One B-rep face of a CAD part: STEP entity #770179.
In plain terms, the planar face has unit normal (0, 0, 1).
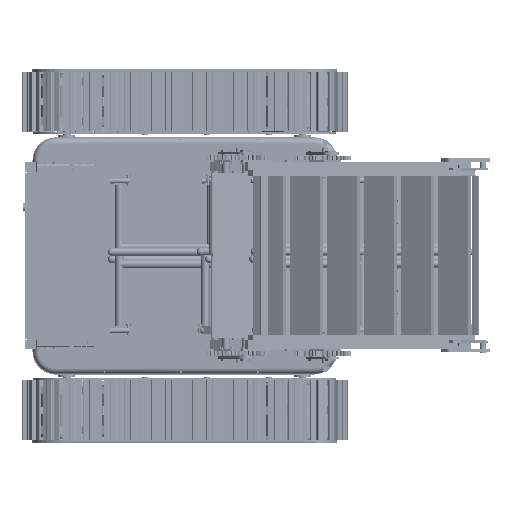
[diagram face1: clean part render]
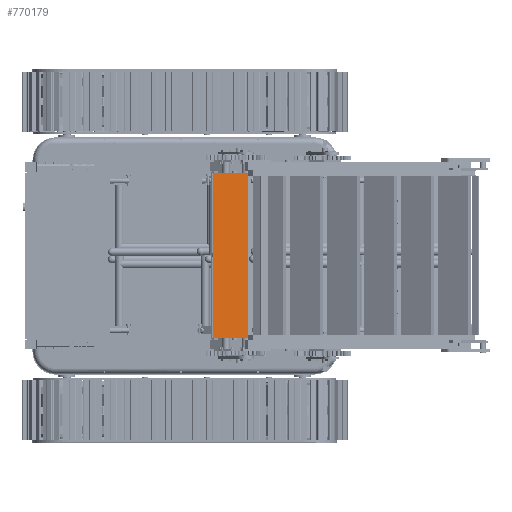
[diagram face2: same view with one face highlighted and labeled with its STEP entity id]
Length unit declared in the file: centimetre
Its self-contained STEP definition (entity closure, numbers rounded to 3 decimals, lengths and spline knots to 4 decimals):
#769865 = VERTEX_POINT('',#769866);
#769866 = CARTESIAN_POINT('',(-19.,-44.,10.));
#769873 = PLANE('',#769874);
#769874 = AXIS2_PLACEMENT_3D('',#769875,#769876,#769877);
#769875 = CARTESIAN_POINT('',(-19.,-44.,9.2));
#769876 = DIRECTION('',(1.,0.,0.));
#769877 = DIRECTION('',(0.,0.,1.));
#769885 = PLANE('',#769886);
#769886 = AXIS2_PLACEMENT_3D('',#769887,#769888,#769889);
#769887 = CARTESIAN_POINT('',(-19.,-44.,9.2));
#769888 = DIRECTION('',(0.,1.,0.));
#769889 = DIRECTION('',(0.,0.,1.));
#769926 = VERTEX_POINT('',#769927);
#769927 = CARTESIAN_POINT('',(-19.,44.,10.));
#769941 = PLANE('',#769942);
#769942 = AXIS2_PLACEMENT_3D('',#769943,#769944,#769945);
#769943 = CARTESIAN_POINT('',(-19.,44.,9.2));
#769944 = DIRECTION('',(0.,1.,0.));
#769945 = DIRECTION('',(0.,0.,1.));
#769953 = EDGE_CURVE('',#769865,#769926,#769954,.T.);
#769954 = SURFACE_CURVE('',#769955,(#769959,#769966),.PCURVE_S1.);
#769955 = LINE('',#769956,#769957);
#769956 = CARTESIAN_POINT('',(-19.,-44.,10.));
#769957 = VECTOR('',#769958,0.1);
#769958 = DIRECTION('',(0.,1.,0.));
#769959 = PCURVE('',#769873,#769960);
#769960 = DEFINITIONAL_REPRESENTATION('',(#769961),#769965);
#769961 = LINE('',#769962,#769963);
#769962 = CARTESIAN_POINT('',(0.8,0.));
#769963 = VECTOR('',#769964,1.);
#769964 = DIRECTION('',(0.,-1.));
#769965 = ( GEOMETRIC_REPRESENTATION_CONTEXT(2) 
PARAMETRIC_REPRESENTATION_CONTEXT() REPRESENTATION_CONTEXT('2D SPACE',''
  ) );
#769966 = PCURVE('',#769967,#769972);
#769967 = PLANE('',#769968);
#769968 = AXIS2_PLACEMENT_3D('',#769969,#769970,#769971);
#769969 = CARTESIAN_POINT('',(-19.,-44.,10.));
#769970 = DIRECTION('',(0.,0.,1.));
#769971 = DIRECTION('',(1.,0.,0.));
#769972 = DEFINITIONAL_REPRESENTATION('',(#769973),#769977);
#769973 = LINE('',#769974,#769975);
#769974 = CARTESIAN_POINT('',(0.,0.));
#769975 = VECTOR('',#769976,1.);
#769976 = DIRECTION('',(0.,1.));
#769977 = ( GEOMETRIC_REPRESENTATION_CONTEXT(2) 
PARAMETRIC_REPRESENTATION_CONTEXT() REPRESENTATION_CONTEXT('2D SPACE',''
  ) );
#769985 = VERTEX_POINT('',#769986);
#769986 = CARTESIAN_POINT('',(0.,-44.,10.));
#769993 = PLANE('',#769994);
#769994 = AXIS2_PLACEMENT_3D('',#769995,#769996,#769997);
#769995 = CARTESIAN_POINT('',(0.,-44.,9.2));
#769996 = DIRECTION('',(1.,0.,0.));
#769997 = DIRECTION('',(0.,0.,1.));
#770036 = VERTEX_POINT('',#770037);
#770037 = CARTESIAN_POINT('',(0.,44.,10.));
#770058 = EDGE_CURVE('',#769985,#770036,#770059,.T.);
#770059 = SURFACE_CURVE('',#770060,(#770064,#770071),.PCURVE_S1.);
#770060 = LINE('',#770061,#770062);
#770061 = CARTESIAN_POINT('',(0.,-44.,10.));
#770062 = VECTOR('',#770063,0.1);
#770063 = DIRECTION('',(0.,1.,0.));
#770064 = PCURVE('',#769993,#770065);
#770065 = DEFINITIONAL_REPRESENTATION('',(#770066),#770070);
#770066 = LINE('',#770067,#770068);
#770067 = CARTESIAN_POINT('',(0.8,0.));
#770068 = VECTOR('',#770069,1.);
#770069 = DIRECTION('',(0.,-1.));
#770070 = ( GEOMETRIC_REPRESENTATION_CONTEXT(2) 
PARAMETRIC_REPRESENTATION_CONTEXT() REPRESENTATION_CONTEXT('2D SPACE',''
  ) );
#770071 = PCURVE('',#769967,#770072);
#770072 = DEFINITIONAL_REPRESENTATION('',(#770073),#770077);
#770073 = LINE('',#770074,#770075);
#770074 = CARTESIAN_POINT('',(19.,0.));
#770075 = VECTOR('',#770076,1.);
#770076 = DIRECTION('',(0.,1.));
#770077 = ( GEOMETRIC_REPRESENTATION_CONTEXT(2) 
PARAMETRIC_REPRESENTATION_CONTEXT() REPRESENTATION_CONTEXT('2D SPACE',''
  ) );
#770104 = EDGE_CURVE('',#769865,#769985,#770105,.T.);
#770105 = SURFACE_CURVE('',#770106,(#770110,#770117),.PCURVE_S1.);
#770106 = LINE('',#770107,#770108);
#770107 = CARTESIAN_POINT('',(-19.,-44.,10.));
#770108 = VECTOR('',#770109,0.1);
#770109 = DIRECTION('',(1.,0.,0.));
#770110 = PCURVE('',#769885,#770111);
#770111 = DEFINITIONAL_REPRESENTATION('',(#770112),#770116);
#770112 = LINE('',#770113,#770114);
#770113 = CARTESIAN_POINT('',(0.8,0.));
#770114 = VECTOR('',#770115,1.);
#770115 = DIRECTION('',(0.,1.));
#770116 = ( GEOMETRIC_REPRESENTATION_CONTEXT(2) 
PARAMETRIC_REPRESENTATION_CONTEXT() REPRESENTATION_CONTEXT('2D SPACE',''
  ) );
#770117 = PCURVE('',#769967,#770118);
#770118 = DEFINITIONAL_REPRESENTATION('',(#770119),#770123);
#770119 = LINE('',#770120,#770121);
#770120 = CARTESIAN_POINT('',(0.,0.));
#770121 = VECTOR('',#770122,1.);
#770122 = DIRECTION('',(1.,0.));
#770123 = ( GEOMETRIC_REPRESENTATION_CONTEXT(2) 
PARAMETRIC_REPRESENTATION_CONTEXT() REPRESENTATION_CONTEXT('2D SPACE',''
  ) );
#770151 = EDGE_CURVE('',#769926,#770036,#770152,.T.);
#770152 = SURFACE_CURVE('',#770153,(#770157,#770164),.PCURVE_S1.);
#770153 = LINE('',#770154,#770155);
#770154 = CARTESIAN_POINT('',(-19.,44.,10.));
#770155 = VECTOR('',#770156,0.1);
#770156 = DIRECTION('',(1.,0.,0.));
#770157 = PCURVE('',#769941,#770158);
#770158 = DEFINITIONAL_REPRESENTATION('',(#770159),#770163);
#770159 = LINE('',#770160,#770161);
#770160 = CARTESIAN_POINT('',(0.8,0.));
#770161 = VECTOR('',#770162,1.);
#770162 = DIRECTION('',(0.,1.));
#770163 = ( GEOMETRIC_REPRESENTATION_CONTEXT(2) 
PARAMETRIC_REPRESENTATION_CONTEXT() REPRESENTATION_CONTEXT('2D SPACE',''
  ) );
#770164 = PCURVE('',#769967,#770165);
#770165 = DEFINITIONAL_REPRESENTATION('',(#770166),#770170);
#770166 = LINE('',#770167,#770168);
#770167 = CARTESIAN_POINT('',(0.,88.));
#770168 = VECTOR('',#770169,1.);
#770169 = DIRECTION('',(1.,0.));
#770170 = ( GEOMETRIC_REPRESENTATION_CONTEXT(2) 
PARAMETRIC_REPRESENTATION_CONTEXT() REPRESENTATION_CONTEXT('2D SPACE',''
  ) );
#770179 = ADVANCED_FACE('',(#770180),#769967,.T.);
#770180 = FACE_BOUND('',#770181,.T.);
#770181 = EDGE_LOOP('',(#770182,#770183,#770184,#770185));
#770182 = ORIENTED_EDGE('',*,*,#769953,.F.);
#770183 = ORIENTED_EDGE('',*,*,#770104,.T.);
#770184 = ORIENTED_EDGE('',*,*,#770058,.T.);
#770185 = ORIENTED_EDGE('',*,*,#770151,.F.);
